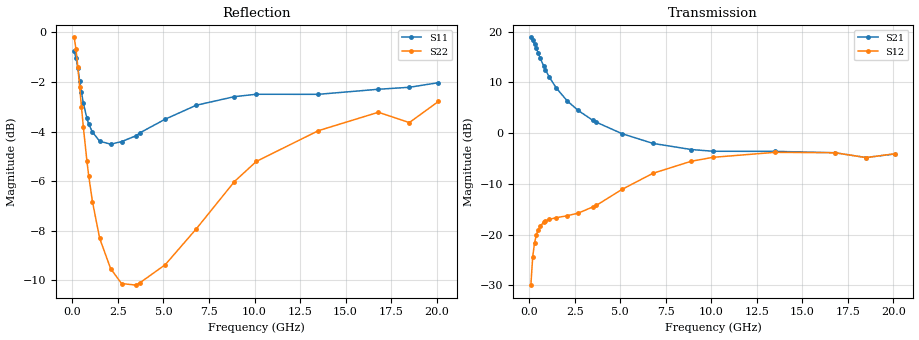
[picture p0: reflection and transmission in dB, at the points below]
!  Infineon Technologies AG
! BFR380L3 , PF131585-7, No.6, Th 09.10.01, soldered on pcb-board, measured with PP GSG850
!  Vce=2.0 V,  Ic=2.5 mA
! Common Emitter S-Parameters:  15. November 2001
#  GHz  S  MA  R  50
! f  S11  S21  S12  S22
! GHz  Mag  Ang  Mag  Ang  Mag  Ang  Mag  Ang
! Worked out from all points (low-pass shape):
!   201 points, 100 MHz to 20.1 GHz, reference 50 ohm
!   highest |S21| = 18.90 dB at 100 MHz (marker M1); lowest = -4.8 dB at 18.5 GHz (marker M2)
!   |S21| within 3 dB of the highest: start of sweep to 490.7 MHz
!   lowest |S11| = -4.5 dB at 2.1 GHz (marker M3), VSWR 3.94, Z = 12.7 - j1.91 ohm
!   |S11| at or under -10 dB: nowhere
!   |S22| runs from -10.2 to -0.2 dB; largest |S21 - S12| = 8.8
!   S11 on the Smith chart (normalised r, x): 100 MHz: 1.38, -5.33; 500 MHz: 0.30, -1.05; 1.1 GHz: 0.26, -0.39; 3.7 GHz: 0.25, +0.26; 8.9 GHz: 0.31, +1.03; 20.1 GHz: 0.96, +2.54
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0.1  0.9154 -20.0  8.813 166.3  0.03166 77.9  0.9768 -11.3
0.2  0.8883 -38.9  8.215 153.7  0.05993 68.4  0.9238 -21.6
0.3  0.8458 -56.5  7.555 142.5  0.0822 59.6  0.8514 -30.3
0.4  0.799 -71.5  6.851 132.9  0.09877 52.5  0.7762 -37.4
0.5  0.7568 -84.7  6.179 124.8  0.1112 47.0  0.7069 -43.1
0.6  0.7203 -96.0  5.574 118.0  0.1202 42.8  0.6454 -47.7
0.8  0.6707 -114.7  4.607 106.8  0.1316 36.8  0.5495 -54.5
0.9  0.6527 -122.3  4.222 102.3  0.1356 34.7  0.5128 -57.0
1.1  0.6296 -135.4  3.609 94.5  0.1409 31.9  0.456 -61.3
1.5  0.6033 -154.9  2.782 82.0  0.1465 30.1  0.3842 -67.7
2.1  0.5951 -175.3  2.077 67.6  0.1533 31.7  0.334 -76.6
2.7  0.6022 169.3  1.674 56.0  0.1626 36.1  0.3117 -86.6
3.5  0.6189 152.9  1.34 42.8  0.187 42.6  0.3094 -100.6
3.7  0.6271 149.6  1.282 40.1  0.1941 43.6  0.3126 -105.1
5.1  0.6683 127.0  0.989 23.1  0.2785 46.9  0.3402 -133.4
6.8  0.7129 105.4  0.7927 9.8  0.4015 39.6  0.4016 -168.8
8.9  0.742 85.5  0.6899 0.3  0.5282 24.2  0.5004 156.5
10.1  0.7502 76.3  0.6629 -3.9  0.5775 14.7  0.5493 138.9
13.5  0.75 58.4  0.6616 -17.8  0.6468 -9.1  0.6334 102.5
16.8  0.7678 47.1  0.6405 -30.3  0.6412 -25.9  0.6901 78.4
18.5  0.7749 45.3  0.5751 -38.3  0.5741 -34.4  0.6578 72.3
20.1  0.7916 38.5  0.6236 -42.2  0.6268 -39.6  0.7256 61.2
